VERSION 5.8 ;
BUSBITCHARS "[]" ;
DIVIDERCHAR "/" ;
UNITS
    DATABASE MICRONS 1000 ;
END UNITS

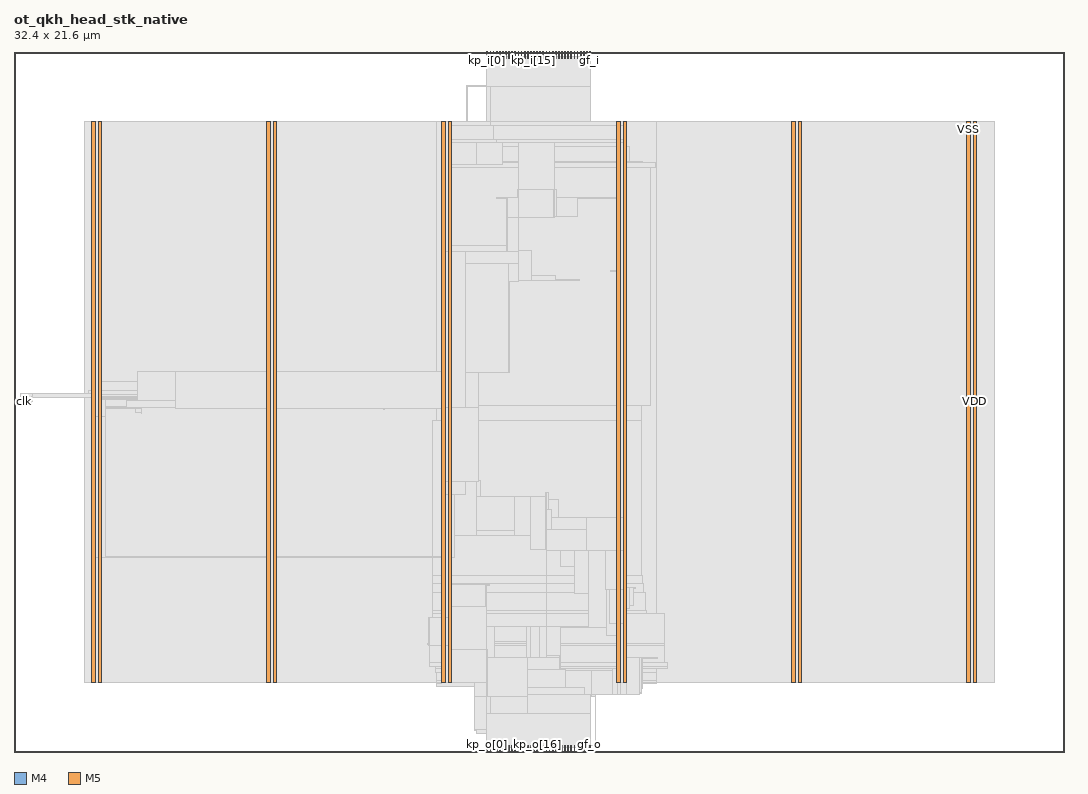
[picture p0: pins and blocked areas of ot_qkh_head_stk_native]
MACRO ot_qkh_head_stk_native
  FOREIGN ot_qkh_head_stk_native 0 0 ;
  CLASS BLOCK ;
  SIZE 32.4 BY 21.6 ;
  PIN clk
    DIRECTION INPUT ;
    USE SIGNAL ;
    PORT
      LAYER M4 ;
        RECT  0 10.8 0.192 10.824 ;
    END
  END clk
  PIN gf_i
    DIRECTION INPUT ;
    USE SIGNAL ;
    PORT
      LAYER M5 ;
        RECT  17.76 21.408 17.784 21.6 ;
    END
  END gf_i
  PIN gf_o
    DIRECTION OUTPUT ;
    USE SIGNAL ;
    PORT
      LAYER M5 ;
        RECT  17.76 0 17.784 0.192 ;
    END
  END gf_o
  PIN kp_i[0]
    DIRECTION INPUT ;
    USE SIGNAL ;
    PORT
      LAYER M5 ;
        RECT  14.592 21.408 14.616 21.6 ;
    END
  END kp_i[0]
  PIN kp_i[10]
    DIRECTION INPUT ;
    USE SIGNAL ;
    PORT
      LAYER M5 ;
        RECT  15.552 21.408 15.576 21.6 ;
    END
  END kp_i[10]
  PIN kp_i[11]
    DIRECTION INPUT ;
    USE SIGNAL ;
    PORT
      LAYER M5 ;
        RECT  15.648 21.408 15.672 21.6 ;
    END
  END kp_i[11]
  PIN kp_i[12]
    DIRECTION INPUT ;
    USE SIGNAL ;
    PORT
      LAYER M5 ;
        RECT  15.744 21.408 15.768 21.6 ;
    END
  END kp_i[12]
  PIN kp_i[13]
    DIRECTION INPUT ;
    USE SIGNAL ;
    PORT
      LAYER M5 ;
        RECT  15.84 21.408 15.864 21.6 ;
    END
  END kp_i[13]
  PIN kp_i[14]
    DIRECTION INPUT ;
    USE SIGNAL ;
    PORT
      LAYER M5 ;
        RECT  15.936 21.408 15.96 21.6 ;
    END
  END kp_i[14]
  PIN kp_i[15]
    DIRECTION INPUT ;
    USE SIGNAL ;
    PORT
      LAYER M5 ;
        RECT  16.032 21.408 16.056 21.6 ;
    END
  END kp_i[15]
  PIN kp_i[16]
    DIRECTION INPUT ;
    USE SIGNAL ;
    PORT
      LAYER M5 ;
        RECT  16.128 21.408 16.152 21.6 ;
    END
  END kp_i[16]
  PIN kp_i[17]
    DIRECTION INPUT ;
    USE SIGNAL ;
    PORT
      LAYER M5 ;
        RECT  16.224 21.408 16.248 21.6 ;
    END
  END kp_i[17]
  PIN kp_i[18]
    DIRECTION INPUT ;
    USE SIGNAL ;
    PORT
      LAYER M5 ;
        RECT  16.32 21.408 16.344 21.6 ;
    END
  END kp_i[18]
  PIN kp_i[19]
    DIRECTION INPUT ;
    USE SIGNAL ;
    PORT
      LAYER M5 ;
        RECT  16.416 21.408 16.44 21.6 ;
    END
  END kp_i[19]
  PIN kp_i[1]
    DIRECTION INPUT ;
    USE SIGNAL ;
    PORT
      LAYER M5 ;
        RECT  14.688 21.408 14.712 21.6 ;
    END
  END kp_i[1]
  PIN kp_i[20]
    DIRECTION INPUT ;
    USE SIGNAL ;
    PORT
      LAYER M5 ;
        RECT  16.512 21.408 16.536 21.6 ;
    END
  END kp_i[20]
  PIN kp_i[21]
    DIRECTION INPUT ;
    USE SIGNAL ;
    PORT
      LAYER M5 ;
        RECT  16.608 21.408 16.632 21.6 ;
    END
  END kp_i[21]
  PIN kp_i[22]
    DIRECTION INPUT ;
    USE SIGNAL ;
    PORT
      LAYER M5 ;
        RECT  16.704 21.408 16.728 21.6 ;
    END
  END kp_i[22]
  PIN kp_i[23]
    DIRECTION INPUT ;
    USE SIGNAL ;
    PORT
      LAYER M5 ;
        RECT  16.8 21.408 16.824 21.6 ;
    END
  END kp_i[23]
  PIN kp_i[24]
    DIRECTION INPUT ;
    USE SIGNAL ;
    PORT
      LAYER M5 ;
        RECT  16.896 21.408 16.92 21.6 ;
    END
  END kp_i[24]
  PIN kp_i[25]
    DIRECTION INPUT ;
    USE SIGNAL ;
    PORT
      LAYER M5 ;
        RECT  16.992 21.408 17.016 21.6 ;
    END
  END kp_i[25]
  PIN kp_i[26]
    DIRECTION INPUT ;
    USE SIGNAL ;
    PORT
      LAYER M5 ;
        RECT  17.088 21.408 17.112 21.6 ;
    END
  END kp_i[26]
  PIN kp_i[27]
    DIRECTION INPUT ;
    USE SIGNAL ;
    PORT
      LAYER M5 ;
        RECT  17.184 21.408 17.208 21.6 ;
    END
  END kp_i[27]
  PIN kp_i[28]
    DIRECTION INPUT ;
    USE SIGNAL ;
    PORT
      LAYER M5 ;
        RECT  17.28 21.408 17.304 21.6 ;
    END
  END kp_i[28]
  PIN kp_i[29]
    DIRECTION INPUT ;
    USE SIGNAL ;
    PORT
      LAYER M5 ;
        RECT  17.376 21.408 17.4 21.6 ;
    END
  END kp_i[29]
  PIN kp_i[2]
    DIRECTION INPUT ;
    USE SIGNAL ;
    PORT
      LAYER M5 ;
        RECT  14.784 21.408 14.808 21.6 ;
    END
  END kp_i[2]
  PIN kp_i[30]
    DIRECTION INPUT ;
    USE SIGNAL ;
    PORT
      LAYER M5 ;
        RECT  17.472 21.408 17.496 21.6 ;
    END
  END kp_i[30]
  PIN kp_i[31]
    DIRECTION INPUT ;
    USE SIGNAL ;
    PORT
      LAYER M5 ;
        RECT  17.568 21.408 17.592 21.6 ;
    END
  END kp_i[31]
  PIN kp_i[3]
    DIRECTION INPUT ;
    USE SIGNAL ;
    PORT
      LAYER M5 ;
        RECT  14.88 21.408 14.904 21.6 ;
    END
  END kp_i[3]
  PIN kp_i[4]
    DIRECTION INPUT ;
    USE SIGNAL ;
    PORT
      LAYER M5 ;
        RECT  14.976 21.408 15 21.6 ;
    END
  END kp_i[4]
  PIN kp_i[5]
    DIRECTION INPUT ;
    USE SIGNAL ;
    PORT
      LAYER M5 ;
        RECT  15.072 21.408 15.096 21.6 ;
    END
  END kp_i[5]
  PIN kp_i[6]
    DIRECTION INPUT ;
    USE SIGNAL ;
    PORT
      LAYER M5 ;
        RECT  15.168 21.408 15.192 21.6 ;
    END
  END kp_i[6]
  PIN kp_i[7]
    DIRECTION INPUT ;
    USE SIGNAL ;
    PORT
      LAYER M5 ;
        RECT  15.264 21.408 15.288 21.6 ;
    END
  END kp_i[7]
  PIN kp_i[8]
    DIRECTION INPUT ;
    USE SIGNAL ;
    PORT
      LAYER M5 ;
        RECT  15.36 21.408 15.384 21.6 ;
    END
  END kp_i[8]
  PIN kp_i[9]
    DIRECTION INPUT ;
    USE SIGNAL ;
    PORT
      LAYER M5 ;
        RECT  15.456 21.408 15.48 21.6 ;
    END
  END kp_i[9]
  PIN kp_o[0]
    DIRECTION OUTPUT ;
    USE SIGNAL ;
    PORT
      LAYER M5 ;
        RECT  14.592 0 14.616 0.192 ;
    END
  END kp_o[0]
  PIN kp_o[10]
    DIRECTION OUTPUT ;
    USE SIGNAL ;
    PORT
      LAYER M5 ;
        RECT  15.552 0 15.576 0.192 ;
    END
  END kp_o[10]
  PIN kp_o[11]
    DIRECTION OUTPUT ;
    USE SIGNAL ;
    PORT
      LAYER M5 ;
        RECT  15.648 0 15.672 0.192 ;
    END
  END kp_o[11]
  PIN kp_o[12]
    DIRECTION OUTPUT ;
    USE SIGNAL ;
    PORT
      LAYER M5 ;
        RECT  15.744 0 15.768 0.192 ;
    END
  END kp_o[12]
  PIN kp_o[13]
    DIRECTION OUTPUT ;
    USE SIGNAL ;
    PORT
      LAYER M5 ;
        RECT  15.84 0 15.864 0.192 ;
    END
  END kp_o[13]
  PIN kp_o[14]
    DIRECTION OUTPUT ;
    USE SIGNAL ;
    PORT
      LAYER M5 ;
        RECT  15.936 0 15.96 0.192 ;
    END
  END kp_o[14]
  PIN kp_o[15]
    DIRECTION OUTPUT ;
    USE SIGNAL ;
    PORT
      LAYER M5 ;
        RECT  16.032 0 16.056 0.192 ;
    END
  END kp_o[15]
  PIN kp_o[16]
    DIRECTION OUTPUT ;
    USE SIGNAL ;
    PORT
      LAYER M5 ;
        RECT  16.128 0 16.152 0.192 ;
    END
  END kp_o[16]
  PIN kp_o[17]
    DIRECTION OUTPUT ;
    USE SIGNAL ;
    PORT
      LAYER M5 ;
        RECT  16.224 0 16.248 0.192 ;
    END
  END kp_o[17]
  PIN kp_o[18]
    DIRECTION OUTPUT ;
    USE SIGNAL ;
    PORT
      LAYER M5 ;
        RECT  16.32 0 16.344 0.192 ;
    END
  END kp_o[18]
  PIN kp_o[19]
    DIRECTION OUTPUT ;
    USE SIGNAL ;
    PORT
      LAYER M5 ;
        RECT  16.416 0 16.44 0.192 ;
    END
  END kp_o[19]
  PIN kp_o[1]
    DIRECTION OUTPUT ;
    USE SIGNAL ;
    PORT
      LAYER M5 ;
        RECT  14.688 0 14.712 0.192 ;
    END
  END kp_o[1]
  PIN kp_o[20]
    DIRECTION OUTPUT ;
    USE SIGNAL ;
    PORT
      LAYER M5 ;
        RECT  16.512 0 16.536 0.192 ;
    END
  END kp_o[20]
  PIN kp_o[21]
    DIRECTION OUTPUT ;
    USE SIGNAL ;
    PORT
      LAYER M5 ;
        RECT  16.608 0 16.632 0.192 ;
    END
  END kp_o[21]
  PIN kp_o[22]
    DIRECTION OUTPUT ;
    USE SIGNAL ;
    PORT
      LAYER M5 ;
        RECT  16.704 0 16.728 0.192 ;
    END
  END kp_o[22]
  PIN kp_o[23]
    DIRECTION OUTPUT ;
    USE SIGNAL ;
    PORT
      LAYER M5 ;
        RECT  16.8 0 16.824 0.192 ;
    END
  END kp_o[23]
  PIN kp_o[24]
    DIRECTION OUTPUT ;
    USE SIGNAL ;
    PORT
      LAYER M5 ;
        RECT  16.896 0 16.92 0.192 ;
    END
  END kp_o[24]
  PIN kp_o[25]
    DIRECTION OUTPUT ;
    USE SIGNAL ;
    PORT
      LAYER M5 ;
        RECT  16.992 0 17.016 0.192 ;
    END
  END kp_o[25]
  PIN kp_o[26]
    DIRECTION OUTPUT ;
    USE SIGNAL ;
    PORT
      LAYER M5 ;
        RECT  17.088 0 17.112 0.192 ;
    END
  END kp_o[26]
  PIN kp_o[27]
    DIRECTION OUTPUT ;
    USE SIGNAL ;
    PORT
      LAYER M5 ;
        RECT  17.184 0 17.208 0.192 ;
    END
  END kp_o[27]
  PIN kp_o[28]
    DIRECTION OUTPUT ;
    USE SIGNAL ;
    PORT
      LAYER M5 ;
        RECT  17.28 0 17.304 0.192 ;
    END
  END kp_o[28]
  PIN kp_o[29]
    DIRECTION OUTPUT ;
    USE SIGNAL ;
    PORT
      LAYER M5 ;
        RECT  17.376 0 17.4 0.192 ;
    END
  END kp_o[29]
  PIN kp_o[2]
    DIRECTION OUTPUT ;
    USE SIGNAL ;
    PORT
      LAYER M5 ;
        RECT  14.784 0 14.808 0.192 ;
    END
  END kp_o[2]
  PIN kp_o[30]
    DIRECTION OUTPUT ;
    USE SIGNAL ;
    PORT
      LAYER M5 ;
        RECT  17.472 0 17.496 0.192 ;
    END
  END kp_o[30]
  PIN kp_o[31]
    DIRECTION OUTPUT ;
    USE SIGNAL ;
    PORT
      LAYER M5 ;
        RECT  17.568 0 17.592 0.192 ;
    END
  END kp_o[31]
  PIN kp_o[3]
    DIRECTION OUTPUT ;
    USE SIGNAL ;
    PORT
      LAYER M5 ;
        RECT  14.88 0 14.904 0.192 ;
    END
  END kp_o[3]
  PIN kp_o[4]
    DIRECTION OUTPUT ;
    USE SIGNAL ;
    PORT
      LAYER M5 ;
        RECT  14.976 0 15 0.192 ;
    END
  END kp_o[4]
  PIN kp_o[5]
    DIRECTION OUTPUT ;
    USE SIGNAL ;
    PORT
      LAYER M5 ;
        RECT  15.072 0 15.096 0.192 ;
    END
  END kp_o[5]
  PIN kp_o[6]
    DIRECTION OUTPUT ;
    USE SIGNAL ;
    PORT
      LAYER M5 ;
        RECT  15.168 0 15.192 0.192 ;
    END
  END kp_o[6]
  PIN kp_o[7]
    DIRECTION OUTPUT ;
    USE SIGNAL ;
    PORT
      LAYER M5 ;
        RECT  15.264 0 15.288 0.192 ;
    END
  END kp_o[7]
  PIN kp_o[8]
    DIRECTION OUTPUT ;
    USE SIGNAL ;
    PORT
      LAYER M5 ;
        RECT  15.36 0 15.384 0.192 ;
    END
  END kp_o[8]
  PIN kp_o[9]
    DIRECTION OUTPUT ;
    USE SIGNAL ;
    PORT
      LAYER M5 ;
        RECT  15.456 0 15.48 0.192 ;
    END
  END kp_o[9]
  PIN kpv_i
    DIRECTION INPUT ;
    USE SIGNAL ;
    PORT
      LAYER M5 ;
        RECT  17.664 21.408 17.688 21.6 ;
    END
  END kpv_i
  PIN kpv_o
    DIRECTION OUTPUT ;
    USE SIGNAL ;
    PORT
      LAYER M5 ;
        RECT  17.664 0 17.688 0.192 ;
    END
  END kpv_o
  PIN rst_n
    DIRECTION INPUT ;
    USE SIGNAL ;
    PORT
      LAYER M4 ;
        RECT  0 10.896 0.192 10.92 ;
    END
  END rst_n
  PIN VDD
    DIRECTION INOUT ;
    USE POWER ;
    PORT
      LAYER M5 ;
        RECT  29.592 2.151 29.712 19.449 ;
        RECT  24.192 2.151 24.312 19.449 ;
        RECT  18.792 2.151 18.912 19.449 ;
        RECT  13.392 2.151 13.512 19.449 ;
        RECT  7.992 2.151 8.112 19.449 ;
        RECT  2.592 2.151 2.712 19.449 ;
    END
  END VDD
  PIN VSS
    DIRECTION INOUT ;
    USE GROUND ;
    PORT
      LAYER M5 ;
        RECT  29.4 2.137 29.52 19.463 ;
        RECT  24 2.137 24.12 19.463 ;
        RECT  18.6 2.137 18.72 19.463 ;
        RECT  13.2 2.137 13.32 19.463 ;
        RECT  7.8 2.137 7.92 19.463 ;
        RECT  2.4 2.137 2.52 19.463 ;
    END
  END VSS
  # OT_OBS_CLOSED layer=M5 d_um=1.536 added=19
  OBS
    LAYER RVTN ;
     RECT  2.16 2.16 30.24 2.295 ;
     RECT  2.16 2.565 30.24 2.835 ;
     RECT  2.16 3.105 30.24 3.375 ;
     RECT  2.16 3.645 30.24 3.915 ;
     RECT  2.16 4.185 30.24 4.455 ;
     RECT  2.16 4.725 30.24 4.995 ;
     RECT  2.16 5.265 30.24 5.535 ;
     RECT  2.16 5.805 30.24 6.075 ;
     RECT  2.16 6.345 30.24 6.615 ;
     RECT  2.16 6.885 30.24 7.155 ;
     RECT  2.16 7.425 30.24 7.695 ;
     RECT  2.16 7.965 30.24 8.235 ;
     RECT  2.16 8.505 30.24 8.775 ;
     RECT  2.16 9.045 30.24 9.315 ;
     RECT  2.16 9.585 30.24 9.855 ;
     RECT  2.16 10.125 30.24 10.395 ;
     RECT  2.16 10.665 30.24 10.935 ;
     RECT  2.16 11.205 30.24 11.475 ;
     RECT  2.16 11.745 30.24 12.015 ;
     RECT  2.16 12.285 30.24 12.555 ;
     RECT  2.16 12.825 30.24 13.095 ;
     RECT  2.16 13.365 30.24 13.635 ;
     RECT  2.16 13.905 30.24 14.175 ;
     RECT  2.16 14.445 30.24 14.715 ;
     RECT  2.16 14.985 30.24 15.255 ;
     RECT  2.16 15.525 30.24 15.795 ;
     RECT  2.16 16.065 30.24 16.335 ;
     RECT  2.16 16.605 30.24 16.875 ;
     RECT  2.16 17.145 30.24 17.415 ;
     RECT  2.16 17.685 30.24 17.955 ;
     RECT  2.16 18.225 30.24 18.495 ;
     RECT  2.16 18.765 30.24 19.035 ;
     RECT  2.16 19.305 30.24 19.44 ;
    LAYER RVTP ;
     RECT  2.16 2.295 30.24 2.565 ;
     RECT  2.16 2.835 30.24 3.105 ;
     RECT  2.16 3.375 30.24 3.645 ;
     RECT  2.16 3.915 30.24 4.185 ;
     RECT  2.16 4.455 30.24 4.725 ;
     RECT  2.16 4.995 30.24 5.265 ;
     RECT  2.16 5.535 30.24 5.805 ;
     RECT  2.16 6.075 30.24 6.345 ;
     RECT  2.16 6.615 30.24 6.885 ;
     RECT  2.16 7.155 30.24 7.425 ;
     RECT  2.16 7.695 30.24 7.965 ;
     RECT  2.16 8.235 30.24 8.505 ;
     RECT  2.16 8.775 30.24 9.045 ;
     RECT  2.16 9.315 30.24 9.585 ;
     RECT  2.16 9.855 30.24 10.125 ;
     RECT  2.16 10.395 30.24 10.665 ;
     RECT  2.16 10.935 30.24 11.205 ;
     RECT  2.16 11.475 30.24 11.745 ;
     RECT  2.16 12.015 30.24 12.285 ;
     RECT  2.16 12.555 30.24 12.825 ;
     RECT  2.16 13.095 30.24 13.365 ;
     RECT  2.16 13.635 30.24 13.905 ;
     RECT  2.16 14.175 30.24 14.445 ;
     RECT  2.16 14.715 30.24 14.985 ;
     RECT  2.16 15.255 30.24 15.525 ;
     RECT  2.16 15.795 30.24 16.065 ;
     RECT  2.16 16.335 30.24 16.605 ;
     RECT  2.16 16.875 30.24 17.145 ;
     RECT  2.16 17.415 30.24 17.685 ;
     RECT  2.16 17.955 30.24 18.225 ;
     RECT  2.16 18.495 30.24 18.765 ;
     RECT  2.16 19.035 30.24 19.305 ;
    LAYER M1 ;
     RECT  2.16 2.151 30.24 19.449 ;
    LAYER M2 ;
     RECT  2.16 2.151 13.027 19.449 ;
     RECT  13.027 2.034 15.431 19.449 ;
     RECT  15.431 2.106 16.043 19.449 ;
     RECT  16.043 2.151 17.311 19.449 ;
     RECT  17.311 2.106 19.823 19.449 ;
     RECT  19.823 2.151 30.24 19.449 ;
    LAYER M3 ;
     RECT  14.868 0.187 14.886 0.235 ;
     RECT  14.868 0.235 15.066 0.571 ;
     RECT  16.416 0.187 16.434 0.571 ;
     RECT  14.292 0.571 16.434 0.667 ;
     RECT  14.22 0.667 16.434 1.723 ;
     RECT  17.928 0.187 17.946 1.723 ;
     RECT  19.26 1.771 19.278 1.819 ;
     RECT  19.26 1.819 19.35 1.867 ;
     RECT  19.224 1.867 19.35 1.915 ;
     RECT  18.9 1.915 19.35 1.963 ;
     RECT  13.032 2.029 13.05 2.101 ;
     RECT  18.9 1.963 19.386 2.101 ;
     RECT  13.032 2.101 13.194 2.143 ;
     RECT  14.22 1.723 17.946 2.143 ;
     RECT  18.9 2.101 19.818 2.143 ;
     RECT  13.032 2.143 13.305 2.191 ;
     RECT  14.22 2.143 19.818 2.191 ;
     RECT  2.415 2.143 2.505 2.413 ;
     RECT  7.815 2.143 7.905 2.413 ;
     RECT  24.015 2.143 24.105 2.413 ;
     RECT  29.415 2.143 29.505 2.413 ;
     RECT  13.032 2.191 19.818 2.461 ;
     RECT  12.996 2.461 19.818 2.569 ;
     RECT  12.996 2.569 20.178 2.641 ;
     RECT  12.816 2.641 20.178 2.759 ;
     RECT  12.816 2.759 20.07 3.301 ;
     RECT  12.78 3.301 20.07 3.341 ;
     RECT  12.924 3.341 20.07 4.289 ;
     RECT  12.924 4.289 19.53 4.379 ;
     RECT  12.924 4.379 19.494 4.919 ;
     RECT  12.924 4.919 19.422 5.189 ;
     RECT  12.924 5.189 19.386 5.459 ;
     RECT  12.924 5.459 19.35 10.229 ;
     RECT  3.924 10.435 3.942 10.471 ;
     RECT  2.415 2.413 2.697 10.597 ;
     RECT  3.744 10.471 3.942 10.597 ;
     RECT  2.415 10.597 3.942 10.633 ;
     RECT  5.004 10.597 5.022 10.633 ;
     RECT  5.796 10.597 5.814 10.633 ;
     RECT  13.215 10.229 19.35 10.705 ;
     RECT  11.412 10.561 11.43 10.831 ;
     RECT  2.415 10.633 5.814 10.895 ;
     RECT  11.34 10.831 11.43 10.895 ;
     RECT  11.34 10.895 11.358 10.925 ;
     RECT  2.415 10.895 5.166 10.931 ;
     RECT  6.84 10.843 6.858 10.973 ;
     RECT  2.415 10.931 5.13 10.975 ;
     RECT  10.764 10.939 10.782 10.976 ;
     RECT  2.412 10.975 5.13 11.035 ;
     RECT  0.216 10.891 0.234 11.069 ;
     RECT  2.304 11.035 5.13 11.165 ;
     RECT  2.415 11.165 5.13 11.435 ;
     RECT  3.816 11.435 5.13 11.669 ;
     RECT  3.816 11.669 4.554 11.705 ;
     RECT  3.816 11.705 4.446 11.741 ;
     RECT  13.215 10.705 19.638 18.031 ;
     RECT  13.215 18.031 19.782 18.185 ;
     RECT  13.215 18.185 19.386 18.221 ;
     RECT  13.215 18.221 18.99 18.689 ;
     RECT  2.415 11.435 2.697 19.187 ;
     RECT  7.815 2.413 8.097 19.187 ;
     RECT  13.215 18.689 18.897 19.187 ;
     RECT  24.015 2.413 24.297 19.187 ;
     RECT  29.415 2.413 29.697 19.187 ;
     RECT  13.215 19.187 18.705 19.229 ;
     RECT  13.215 19.229 17.766 19.277 ;
     RECT  13.215 19.277 17.658 19.379 ;
     RECT  2.415 19.187 2.505 19.457 ;
     RECT  7.815 19.187 7.905 19.457 ;
     RECT  13.215 19.379 13.986 19.457 ;
     RECT  18.615 19.229 18.705 19.457 ;
     RECT  24.015 19.187 24.105 19.457 ;
     RECT  29.415 19.187 29.505 19.457 ;
     RECT  13.968 19.457 13.986 20.573 ;
     RECT  14.796 19.379 14.814 20.573 ;
     RECT  15.948 19.379 16.434 20.573 ;
    LAYER M4 ;
     RECT  0.156 10.8 0.205 10.92 ;
     RECT  0.205 10.8 0.563 11.064 ;
     RECT  0.563 10.944 2.408 11.064 ;
     RECT  2.408 2.148 2.512 19.452 ;
     RECT  2.512 2.418 2.704 19.182 ;
     RECT  2.704 10.32 2.819 10.872 ;
     RECT  2.819 10.656 3.485 10.872 ;
     RECT  3.485 10.848 3.805 10.872 ;
     RECT  3.805 10.848 4.993 11.736 ;
     RECT  2.704 6 7.808 6.024 ;
     RECT  4.993 10.608 7.808 11.736 ;
     RECT  7.808 2.148 7.912 19.452 ;
     RECT  7.912 2.418 8.104 19.182 ;
     RECT  12.764 3.312 12.805 3.336 ;
     RECT  12.805 3.312 13.208 4.152 ;
     RECT  8.104 6 13.208 6.024 ;
     RECT  8.104 10.608 13.208 11.736 ;
     RECT  13.208 2.148 13.312 19.452 ;
     RECT  13.312 2.418 13.504 19.182 ;
     RECT  13.504 6 13.601 8.376 ;
     RECT  13.504 10.608 13.955 11.736 ;
     RECT  14.209 0.672 14.281 0.696 ;
     RECT  13.504 18.144 14.281 19.182 ;
     RECT  13.601 6.672 14.285 8.376 ;
     RECT  13.955 10.608 14.339 10.632 ;
     RECT  14.285 7.872 14.38 8.376 ;
     RECT  13.504 3.024 14.492 4.152 ;
     RECT  14.492 3.024 14.533 4.536 ;
     RECT  14.533 3.024 14.569 5.16 ;
     RECT  14.569 2.928 14.579 5.16 ;
     RECT  14.579 5.136 14.681 5.16 ;
     RECT  14.636 1.68 14.723 1.704 ;
     RECT  14.281 0.576 14.821 0.696 ;
     RECT  14.579 2.928 14.825 3.864 ;
     RECT  14.821 0.576 14.857 1.176 ;
     RECT  14.281 18.144 15.077 19.368 ;
     RECT  13.504 14.688 15.205 15.624 ;
     RECT  14.893 17.088 15.205 17.112 ;
     RECT  13.955 11.712 15.299 11.736 ;
     RECT  15.205 14.688 15.365 17.112 ;
     RECT  14.857 0.192 15.409 1.176 ;
     RECT  14.285 6.672 15.433 6.84 ;
     RECT  14.38 7.872 15.433 7.896 ;
     RECT  15.409 0.192 15.491 0.696 ;
     RECT  15.365 14.688 15.541 15.48 ;
     RECT  15.365 16.512 15.541 17.112 ;
     RECT  15.541 16.512 15.628 17.352 ;
     RECT  15.491 0.192 15.805 0.648 ;
     RECT  14.825 3.408 15.829 3.864 ;
     RECT  15.829 2.88 15.925 3.864 ;
     RECT  15.433 6.672 15.937 7.896 ;
     RECT  15.541 14.544 15.977 15.48 ;
     RECT  15.805 0.192 16.093 0.6 ;
     RECT  15.925 2.16 16.213 3.864 ;
     RECT  15.937 6.24 16.405 7.896 ;
     RECT  16.093 0.192 16.489 0.216 ;
     RECT  16.405 6.24 16.489 7.992 ;
     RECT  13.957 20.544 16.643 20.568 ;
     RECT  15.628 16.512 16.645 17.112 ;
     RECT  15.977 14.544 16.697 14.712 ;
     RECT  16.645 16.512 16.732 17.352 ;
     RECT  16.489 6.24 16.805 7.8 ;
     RECT  16.805 6.24 16.873 7.224 ;
     RECT  16.213 1.728 16.877 3.864 ;
     RECT  16.873 5.712 17.305 7.224 ;
     RECT  16.732 16.512 17.381 17.112 ;
     RECT  16.697 14.544 17.453 14.568 ;
     RECT  16.877 3.84 17.737 3.864 ;
     RECT  17.305 4.896 17.737 7.224 ;
     RECT  16.877 1.728 17.813 2.52 ;
     RECT  17.653 0.192 17.957 0.216 ;
     RECT  17.737 3.84 18.277 7.224 ;
     RECT  17.813 1.776 18.457 2.52 ;
     RECT  18.457 1.776 18.608 2.568 ;
     RECT  18.277 3.6 18.608 7.224 ;
     RECT  18.421 14.832 18.608 14.856 ;
     RECT  17.381 17.088 18.608 17.112 ;
     RECT  15.077 18.816 18.608 19.368 ;
     RECT  18.608 1.776 18.712 19.452 ;
     RECT  18.712 1.776 18.904 19.182 ;
     RECT  18.904 4.416 19.001 5.064 ;
     RECT  19.001 4.512 19.109 5.064 ;
     RECT  19.109 5.04 19.181 5.064 ;
     RECT  18.904 1.776 19.289 2.904 ;
     RECT  19.289 1.824 19.361 2.904 ;
     RECT  19.361 1.968 19.397 2.904 ;
     RECT  19.397 2.88 19.865 2.904 ;
     RECT  24.008 2.148 24.112 19.452 ;
     RECT  24.112 2.418 24.304 19.182 ;
     RECT  29.408 2.148 29.512 19.452 ;
     RECT  29.512 2.418 29.704 19.182 ;
    LAYER M5 ;
     RECT  14.592 0.144 17.784 1.187 ;
     RECT  14.592 1.187 14.712 1.715 ;
     RECT  15.84 1.187 17.784 1.763 ;
     RECT  15.84 1.763 17.592 2.003 ;
     RECT  2.4 2.137 2.52 2.151 ;
     RECT  7.8 2.137 7.92 2.151 ;
     RECT  13.2 2.137 13.32 2.151 ;
     RECT  18.6 2.137 18.72 2.151 ;
     RECT  24 2.137 24.12 2.151 ;
     RECT  29.4 2.137 29.52 2.151 ;
     RECT  15.84 2.003 17.016 2.531 ;
     RECT  15.84 2.531 16.824 2.915 ;
     RECT  16.416 2.915 16.824 2.963 ;
     RECT  14.592 1.715 14.616 3.155 ;
     RECT  13.2 2.151 13.512 3.301 ;
     RECT  18.6 2.151 18.912 3.973 ;
     RECT  12.816 3.301 13.512 4.163 ;
     RECT  18.384 3.973 18.912 5.029 ;
     RECT  14.544 4.501 14.568 5.171 ;
     RECT  2.4 2.151 2.712 5.989 ;
     RECT  18.24 5.029 18.912 6.229 ;
     RECT  16.416 2.963 16.44 6.853 ;
     RECT  17.664 6.229 18.912 7.235 ;
     RECT  16.416 6.853 16.584 7.475 ;
     RECT  13.2 4.163 13.512 7.957 ;
     RECT  16.416 7.475 16.44 8.003 ;
     RECT  13.2 7.957 13.944 8.341 ;
     RECT  2.4 5.989 2.808 10.355 ;
     RECT  13.2 8.341 14.328 10.643 ;
     RECT  0.528 10.789 0.552 10.979 ;
     RECT  15.264 11.701 15.288 14.533 ;
     RECT  15.264 14.533 15.576 15.059 ;
     RECT  13.2 10.643 13.944 15.443 ;
     RECT  15.552 15.059 15.576 16.501 ;
     RECT  15.216 16.501 15.576 17.123 ;
     RECT  15.552 17.123 15.576 17.363 ;
     RECT  16.656 16.501 16.68 17.363 ;
     RECT  18.6 7.235 18.912 18.805 ;
     RECT  14.88 18.805 18.912 18.901 ;
     RECT  14.784 18.901 18.912 19.333 ;
     RECT  2.4 10.355 2.712 19.449 ;
     RECT  7.8 2.151 8.112 19.449 ;
     RECT  13.2 15.443 13.512 19.449 ;
     RECT  14.688 19.333 18.912 19.449 ;
     RECT  24 2.151 24.312 19.449 ;
     RECT  29.4 2.151 29.712 19.449 ;
     RECT  2.4 19.449 2.52 19.463 ;
     RECT  7.8 19.449 7.92 19.463 ;
     RECT  13.2 19.449 13.32 19.463 ;
     RECT  14.688 19.449 18.72 19.463 ;
     RECT  24 19.449 24.12 19.463 ;
     RECT  29.4 19.449 29.52 19.463 ;
     RECT  14.688 19.463 17.784 20.533 ;
     RECT  14.592 20.533 17.784 21.456 ;
     RECT  14.712 1.187 15.84 1.715 ;
     RECT  14.616 1.715 15.84 2.915 ;
     RECT  13.32 2.137 14.592 2.151 ;
     RECT  13.512 2.151 14.592 3.155 ;
     RECT  13.512 3.155 14.568 4.501 ;
     RECT  13.512 4.501 14.544 5.171 ;
     RECT  16.44 6.229 17.664 6.853 ;
     RECT  16.584 6.853 17.664 7.235 ;
     RECT  13.944 10.643 14.328 11.701 ;
     RECT  13.944 11.701 15.264 15.059 ;
     RECT  13.944 15.059 15.552 15.443 ;
     RECT  15.216 15.443 15.552 16.501 ;
     RECT  15.576 16.501 16.656 17.363 ;
     RECT  15.552 17.363 16.68 18.805 ;
     RECT  13.512 18.805 14.88 18.901 ;
     RECT  13.512 18.901 14.784 19.333 ;
     RECT  13.512 19.333 14.688 19.449 ;
     RECT  13.32 19.449 14.688 19.463 ;
     RECT  14.592 19.463 14.688 20.533 ;
  END
END ot_qkh_head_stk_native
END LIBRARY
